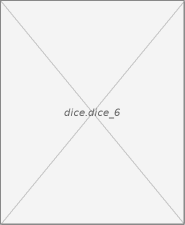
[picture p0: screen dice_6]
VISUALIZATION dice_6  // 185x225
VAR_IN_OUT
VAR_IN_OUT
	
END_VAR
    Image (0,0 185x225), image: dice.dice_6
END_VISUALIZATION
